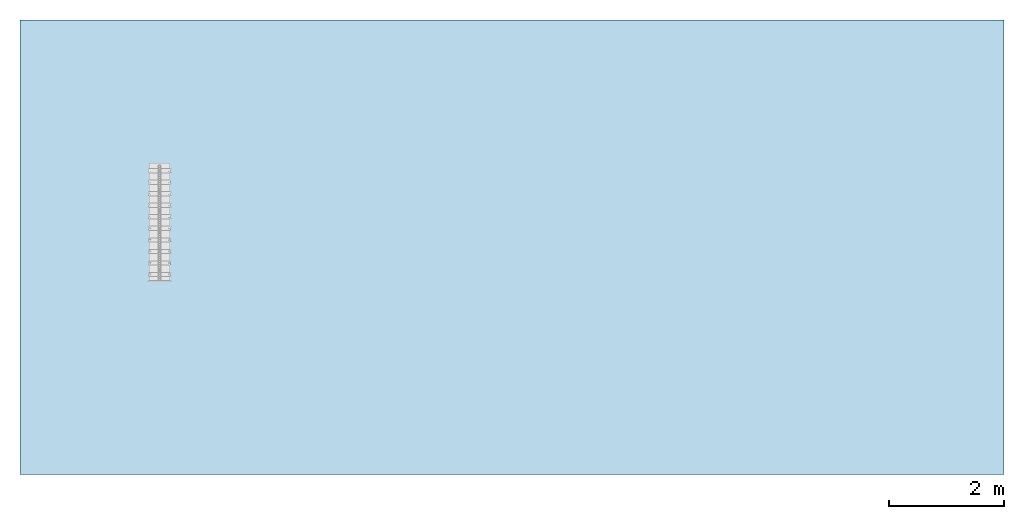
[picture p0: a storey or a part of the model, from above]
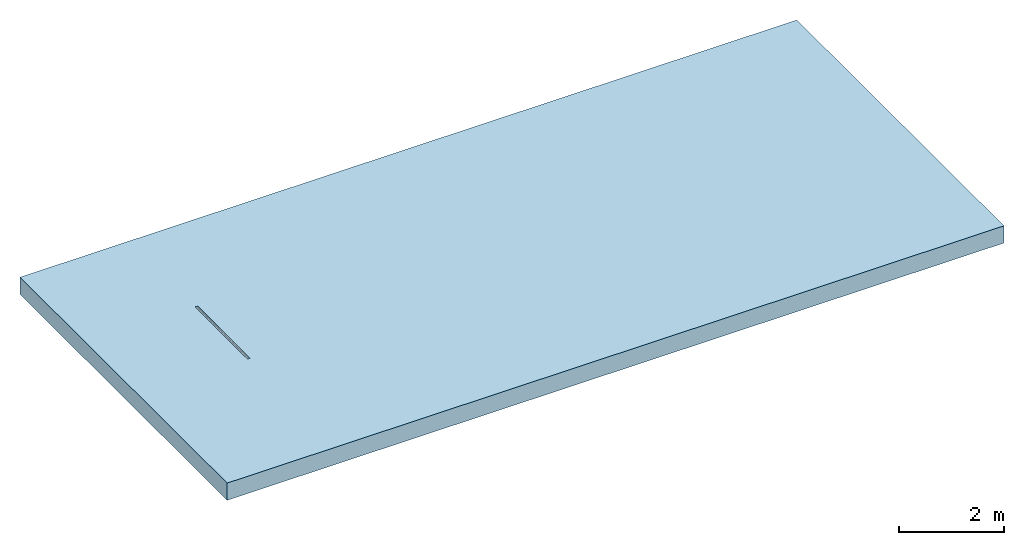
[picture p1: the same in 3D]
Properties of the parts of a building model (IFC2X3)

# File
Description: ViewDefinition [CoordinationView]
File name: 32813 - Q-Guard Edge - G.S.ifc
Time: 2013-07-12T11:21:53
Written by: Autodesk Revit 2013
Made in: 20120221_2030(x64)

# IfcProject, Project Number
LongName: Project Name; Phase: Project Status

# IfcSite, Default
RefLatitude: 42, 21, 30, 344238; RefLongitude: -71, -3, -35, -194702; RefElevation: 0 mm

# IfcBuilding
Pset_BuildingCommon - NumberOfStoreys: 1
Other - Project Status: Project Status; Project Name: Project Name; Project Issue Date: Issue Date; Project Number: Project Number; Project Address: ## Street City, State Zip; Client Name: Owner

# IfcBuildingStorey, Level 1
LongName: Level 1; Elevation: 0 mm
Constraints - Elevation Base: 0; Elevation: 0 mm
Graphics - Color: 0; Symbol: M_Level Head - Circle: M_Level Head - Circle; Symbol at End 1 Default: no; Symbol at End 2 Default: yes; Line Weight: 1; Line Pattern: Center
Dimensions - Computation Height: 0 mm
Identity Data - Structural: no; Name: Level 1; Building Story: yes

# IfcFlowTerminal: 32813 - Q-Guard Edge - G.S, Qmax 350:32813 - Q-Guard Edge - G.S:32813 - Q-Guard Edge - G.S:562865
In: Level 1
Constraints - Level: Level: Level 1; Moves With Nearby Elements: no
Phasing - Phase Created: New Construction
Identity Data - Mark: 40; Product Code: 32813; Product Page URL: http://www.aco.co.uk/product_detail.php?id=79; OmniClass Number: 23.70.50.24; Assembly Description: Rain Water Drainage; URL: www.aco.co.uk; Cost: 0; Manufacturer: ACO Technologies plc - ACO Water Management Division; Model Description: High capacity slot drainage channel system; e-mail Technical: technical@aco.co.uk; Price: POA - contact ACO; Telephone: +44 (0) 1462 816666; Product Brochure: http://www.aco.co.uk/download.php?id=220; Assembly Code: D2040; Maintenance Guidelines: http://www.aco.co.uk/download.php?id=220; OmniClass Title: Rainwater Removal; Model: ACO Qmax 350; Address: ACO Business Park, Hitchin Road, Bedfordshire, United Kingdom SG17 5TE; Fax: +44 (0) 1462 815895; Type Comments: ACO Qmax 350 channel assembly complete with ACO Q-Guard galvanised steel edge rail; e-mail Sales: customersupport@aco.co.uk; Installation Guidelines: http://www.aco.co.uk/download.php?id=220
Construction - 42351_350 End Cap (Female end): no; 32880_225-350 Step Connector: no; 42351_350 End Cap (Male end): no; V_Coarse_E5: no; E2-QGuard-DuctileIron: no; E5-QSlot-GalvSteel: no; V_CoarseE1: yes; E4-QGuard-GalvSteel: yes; E3-QFlow-GalvSteel: no; E1-QFlow-DuctileIron: no
Model Properties - 225-350 Step Connector - Dimensions: Ø435mm x 25mm (ØxL); Multi-Functional End Cap - Channel Recycled Material Content: Variable %; Multi-Functional End Cap - Seal Recycled Material Content: 0%; Multi-Functional End Cap - Channel Material: Medium Density Polyethylene; Multi-Functional End Cap - Product Code: 42351; 225-350 Step Connector - Material: High Density Polyethylene; Multi-Functional End Cap - Dimensions: Ø435mm x 260mm (ØxL); 225-350 Step Connector - Model Description: High capacity slot drainage channel system; Multi-Functional End Cap - Channel Recyclable: Fully recyclable; 225-350 Step Connector - Recycled Material Content: 0%; Multi-Functional End Cap - Model Description: High capacity slot drainage channel system; 225-350 Step Connector - Product Code: 32880; Multi-Functional End Cap - Weight: 2.6 kg; 225-350 Step Connector - Recyclable: Fully recyclable; Multi-Functional End Cap - Seal Material: Chloroprene; Multi-Functional End Cap - Channel Colour: Black; 225-350 Step Connector- Colour: Black; Multi-Functional End Cap - Seal Recyclable: Fully recyclable Fully recyclable; Multi-Functional End Cap - Seal Colour: Black; 225-350 Step Connector - Weight: 0.8 kg
General - TagNumber: 0; SerialNumber: 0
Data - Drainage Slot Width: 10mm; Product Standard: BS EN 1433:2002 CE marked; Product Weight: 21.5 kg; Concrete Surround Volume - Load Class A 15 - E 600: 0.34 m³/m; Installation - Reinforcement Details: Refer to brochure; Drainage Slot Intake Area: 8356mm²/m; Channel C.S.A: 96211mm²; Invert Depth: 550mm; Concrete Surround Volume - Load Class F 900: 0.45 m³/m; Installation - Concrete Grade: Refer to brochure; Hydraulic Performance: http://www.aco.co.uk/download.php?id=220; Load Class: A15 - F 900; ACO Hydraulic Design Software: http://www.acodesign.co.uk; Product Dimensions: 2000mm x 415mm x 600mm (LxWxH)
Materials and Finishes - Seal Material: Chloroprene; Channel Colour: Black; Channel Material: Medium Density Polyethylene; Seal Colour: Black; Edge Rail Colour: Silver; Edge Rail Finish: Galvanised; Edge Rail Material: Steel
Green Building Properties - Edge Rail Recyclable: Fully recyclable; Channel Recyclable: Fully recyclable; Seal Recyclable: Fully recyclable; Edge Rail Recycled Material Content: Between 40% - 90%; Channel Recycled Material Content: Variable %; Seal Recycled Material Content: 0%
Dimensions - Length: 2000 mm; Floor Opening Width: 55 mm; Depth Overall: 600 mm; BoreCentre: 370 mm; Width Overall: 415 mm
Other - Revision: 1; Created by: www.aco.co.uk

# IfcOpeningElement: Opening
In: Level 1
Phasing - Phase Created: New Construction
Dimensions - Volume: 53725600000 mm3; Area: 134980000 mm2; Perimeter: 50000 mm; Thickness: 400 mm
Constraints - Height Offset From Level: 0 mm; Level: Level: Level 1; Room Bounding: yes; Related to Mass: no
Structural - Enable Analytical Model: no; Structural: no
Construction - Default Thickness: 400 mm; Function: 0
Graphics - Coarse Scale Fill Color: 0
Analytical Properties - Absorptance: 0.1; Roughness: 1
Materials and Finishes - Structural Material: Plant

# IfcSlab: Floor:Generic Floor - 400mm, Floor:Generic Floor - 400mm:193825
In: Level 1
PredefinedType: FLOOR; Material: Plant 400 mm
Phasing - Phase Created: New Construction
Dimensions - Volume: 53725600000 mm3; Area: 134980000 mm2; Perimeter: 50000 mm; Thickness: 400 mm
Constraints - Height Offset From Level: 0 mm; Level: Level: Level 1; Room Bounding: yes; Related to Mass: no
Structural - Enable Analytical Model: no; Structural: no
Pset_SlabCommon - Reference: Generic Floor - 400mm; IsExternal: no; LoadBearing: yes
Construction - Default Thickness: 400 mm; Function: 0
Graphics - Coarse Scale Fill Color: 0
Analytical Properties - Absorptance: 0.1; Roughness: 1
Materials and Finishes - Structural Material: Plant
